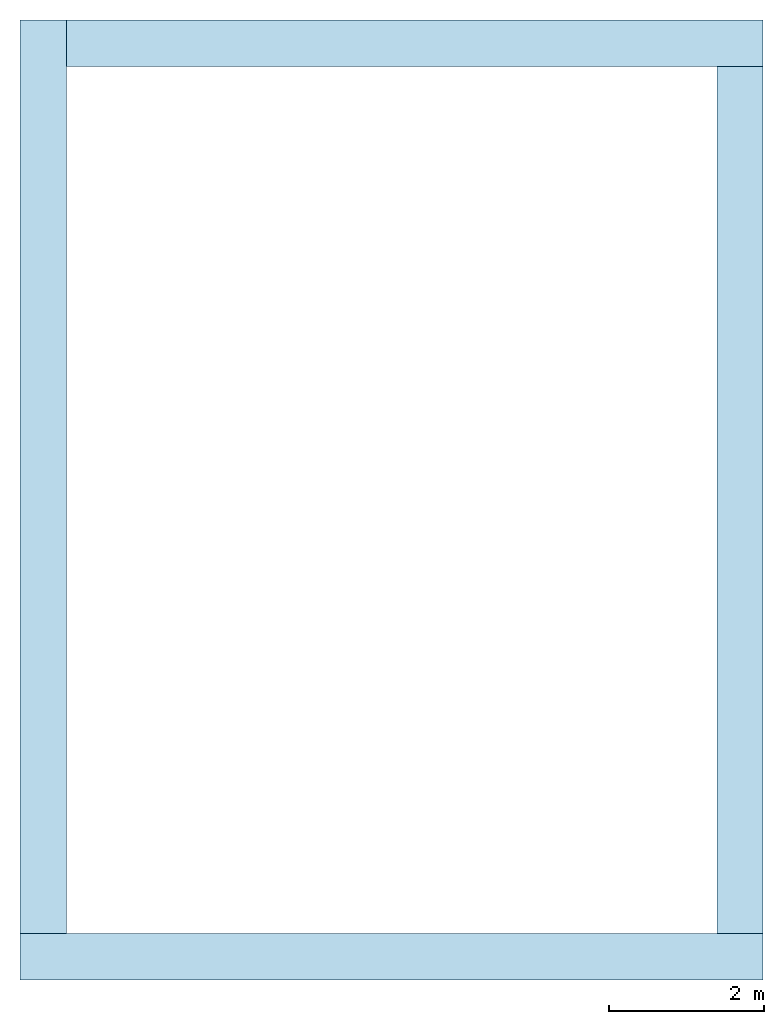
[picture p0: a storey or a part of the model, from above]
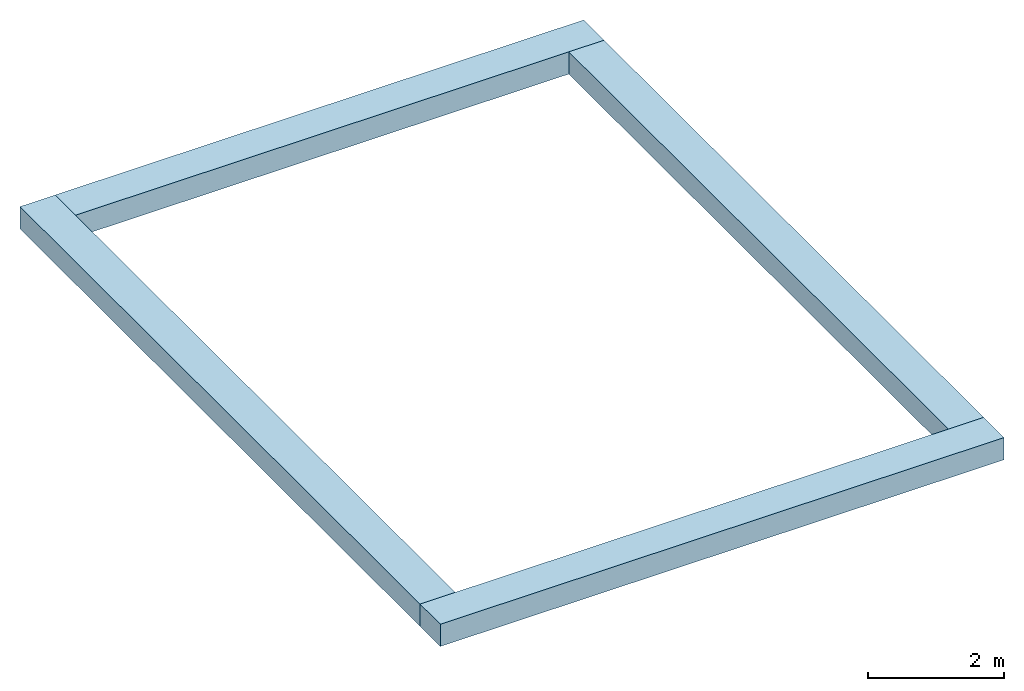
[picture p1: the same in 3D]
Properties of the parts of a building model (IFC2X3)

# File
Description: ViewDefinition [CoordinationView_V2.0], RevitIdentifiers [VersionGUID: 7e6f9387-9621-4ef8-beaa-c9e1d8378c29, NumberOfSaves: 130], CoordinateReference [CoordinateBase: Coordonnées partagées]
File name: 313 AD 1116
Time: 2024-11-04T11:44:57+01:00
Written by: ODA SDAI 23.12
Made in: Autodesk Revit 24.0.5.432 (FRA) - IFC 24.0.5.432

# IfcProject, 313 AD 1116
Phase: Etat du projet

# IfcSite, Default
RefLatitude: 42, 12, 46, 804504; RefLongitude: -71, -2, 0, -602416; RefElevation: 0 m

# IfcBuilding, MAISON D'HABITATION
LongName: MAISON D'HABITATION
Pset_BuildingCommon - NumberOfStoreys: 9

# IfcBuildingStorey: Niveau:Pointe 8 mm (14)
In: MAISON D'HABITATION
Name | LongName | Elevation (m)
Niveau .... | Niveau .... | -0.230224
Niveau ... | Niveau ... | -0.160224
Niveau .. | Niveau .. | -0.110224
Niveau dessus semelle filante | Niveau dessus semelle filante | 0.389776
Plan Réseau | Plan Réseau | 0.880776
Niveau Dalle ↑ | Niveau Dalle ↑ | 0.909776
Niveau Arase 9 | Niveau Arase 9 | 0.909776
site | site | 1.03978
Niveau coupe Menuiserie ↑ | Niveau coupe Menuiserie ↑ | 2.18978
Niveau Linteau | Niveau Linteau | 3.18978
Niveau plafond ↓ | Niveau plafond ↓ | 3.53978
Niveau ..... | Niveau ..... | 3.56978
Niveau toiture etage | Niveau toiture etage | 6.06978
Surface habitable | Surface habitable | 6.73438

# IfcSpace: Buanderie 08:3480308, 08
In: site
LongName: Buanderie; InteriorOrExteriorSpace: INTERNAL
Pset_SpaceCommon - Reference: Buanderie 08

# IfcSpace: Bureau 02:2227268, 02
In: site
LongName: Bureau; InteriorOrExteriorSpace: INTERNAL
Pset_SpaceCommon - Reference: Bureau 02

# IfcSpace: CH -1- 01:2227259, 01
In: site
LongName: CH -1-; InteriorOrExteriorSpace: INTERNAL
Pset_SpaceCommon - Reference: CH -1- 01

# IfcSpace: Dég -1- 05:2227277, 05
In: site
LongName: Dég -1-; InteriorOrExteriorSpace: INTERNAL
Pset_SpaceCommon - Reference: Dég -1- 05

# IfcSpace: Emprise au sol 09:3095654, 09
In: Niveau toiture etage
LongName: Emprise au sol; InteriorOrExteriorSpace: INTERNAL
Pset_SpaceCommon - Reference: Emprise au sol 09

# IfcSpace: Garage 07:2811163, 07
In: site
LongName: Garage; InteriorOrExteriorSpace: INTERNAL
Pset_SpaceCommon - Reference: Garage 07

# IfcSpace: SaM/Salon/Cuisine 06:2227850, 06
In: site
LongName: SaM/Salon/Cuisine; InteriorOrExteriorSpace: INTERNAL
Pset_SpaceCommon - Reference: SaM/Salon/Cuisine 06

# IfcSpace: SdB -1- 03:2227262, 03
In: site
LongName: SdB -1-; InteriorOrExteriorSpace: INTERNAL
Pset_SpaceCommon - Reference: SdB -1- 03

# IfcSpace: Surface Plancher 08:3095472, 08
In: Niveau ...
LongName: Surface Plancher; InteriorOrExteriorSpace: INTERNAL
Pset_SpaceCommon - Reference: Surface Plancher 08

# IfcSpace: Toilette 04:2227265, 04
In: site
LongName: Toilette; InteriorOrExteriorSpace: INTERNAL
Pset_SpaceCommon - Reference: Toilette 04

# IfcBuildingElementProxy: Bord de dalle:Bord des dalles, Bord de dalle:Bord des dalles:3095911
In: Plan Réseau
Pset_BuildingElementProxyCommon - Reference: Bord des dalles; sets with these values: 2

# IfcBuildingElementProxy: Bord de toiture:Bord de toiture DROIT, Bord de toiture:Bord de toiture DROIT:3165497
In: Niveau .....
Pset_BuildingElementProxyCommon - Reference: Bord de toiture DROIT; sets with these values: 2
Pset_ProvisionForVoid - Shape: Undefined; Width: 12.04 m; Height: 0.019 m; Depth: 0.019 m

# IfcBuildingElementProxy: Ossature 10:Ossature 1, Ossature 10:Ossature 1:3317750
In: Niveau .....
Type - Material: <Unnamed>
Pset_BuildingElementProxyCommon - Reference: Ossature 1; sets with these values: 2
Group: Groupe de modèles:Groupe de réseaux 2:3317774

# IfcBuildingElementProxy: Ossature 11:Ossature 1, Ossature 11:Ossature 1:3317780
In: Niveau .....
Type - Material: <Unnamed>
Pset_BuildingElementProxyCommon - Reference: Ossature 1; sets with these values: 2
Group: Groupe de modèles:Groupe de réseaux 2:3317804

# IfcBuildingElementProxy: Ossature 12:Ossature 1, Ossature 12:Ossature 1:3317810
In: Niveau .....
Type - Material: <Unnamed>
Pset_BuildingElementProxyCommon - Reference: Ossature 1; sets with these values: 2
Group: Groupe de modèles:Groupe de réseaux 2:3317834

# IfcBuildingElementProxy: Ossature 13:Ossature 1, Ossature 13:Ossature 1:3317840
In: Niveau .....
Type - Material: <Unnamed>
Pset_BuildingElementProxyCommon - Reference: Ossature 1; sets with these values: 2

# IfcBuildingElementProxy: Ossature 14:Ossature 1, Ossature 14:Ossature 1:3317870
In: Niveau .....
Type - Material: <Unnamed>
Pset_BuildingElementProxyCommon - Reference: Ossature 1; sets with these values: 2

# IfcBuildingElementProxy: Ossature 15:Ossature 1, Ossature 15:Ossature 1:3166287
In: Niveau .....
Type - Material: <Unnamed>
Pset_BuildingElementProxyCommon - Reference: Ossature 1; sets with these values: 2
Group: Groupe de modèles:Groupe de réseaux 2:3317463

# IfcBuildingElementProxy: Ossature 16:Ossature 16, Ossature 16:Ossature 16:3168144
In: Niveau .....
Type - Material: <Unnamed>
Pset_BuildingElementProxyCommon - Reference: Ossature 16; sets with these values: 2
Pset_ProvisionForVoid - Width: 0.253567 m; Height: 0.08 m; Depth: 0.08 m

# IfcBuildingElementProxy: Ossature 17:Ossature 17, Ossature 17:Ossature 17:2951754
In: Niveau .....
Type - Material: <Unnamed>
Pset_BuildingElementProxyCommon - Reference: Ossature 17; sets with these values: 2
Pset_ProvisionForVoid - Width: 0.05 m; Height: 0.05 m; Depth: 0.05 m

# IfcBuildingElementProxy: Ossature 18:Ossature 1, Ossature 18:Ossature 1:3317900
In: Niveau .....
Type - Material: <Unnamed>
Pset_BuildingElementProxyCommon - Reference: Ossature 1; sets with these values: 2
Group: Groupe de modèles:Groupe de réseaux 2:3317924

# IfcBuildingElementProxy: Ossature 1:Ossature 1, Ossature 1:Ossature 1:3317470
In: Niveau .....
Type - Material: <Unnamed>
Pset_BuildingElementProxyCommon - Reference: Ossature 1; sets with these values: 2
Group: Groupe de modèles:Groupe de réseaux 2:3317494

# IfcBuildingElementProxy: Ossature 2:Ossature 1, Ossature 2:Ossature 1:3317540
In: Niveau .....
Type - Material: <Unnamed>
Pset_BuildingElementProxyCommon - Reference: Ossature 1; sets with these values: 2
Group: Groupe de modèles:Groupe de réseaux 2:3317564

# IfcBuildingElementProxy: Ossature 3:Ossature 1, Ossature 3:Ossature 1:3317570
In: Niveau .....
Type - Material: <Unnamed>
Pset_BuildingElementProxyCommon - Reference: Ossature 1; sets with these values: 2
Group: Groupe de modèles:Groupe de réseaux 2:3317594

# IfcBuildingElementProxy: Ossature 5:Ossature 1, Ossature 5:Ossature 1:3317600
In: Niveau .....
Type - Material: <Unnamed>
Pset_BuildingElementProxyCommon - Reference: Ossature 1; sets with these values: 2

# IfcBuildingElementProxy: Ossature 6:Ossature 1, Ossature 6:Ossature 1:3317630
In: Niveau .....
Type - Material: <Unnamed>
Pset_BuildingElementProxyCommon - Reference: Ossature 1; sets with these values: 2
Group: Groupe de modèles:Groupe de réseaux 2:3317654

# IfcBuildingElementProxy: Ossature 7:Ossature 1, Ossature 7:Ossature 1:3317660
In: Niveau .....
Type - Material: <Unnamed>
Pset_BuildingElementProxyCommon - Reference: Ossature 1; sets with these values: 2
Group: Groupe de modèles:Groupe de réseaux 2:3317684

# IfcBuildingElementProxy: Ossature 8:Ossature 1, Ossature 8:Ossature 1:3317690
In: Niveau .....
Type - Material: <Unnamed>
Pset_BuildingElementProxyCommon - Reference: Ossature 1; sets with these values: 2
Group: Groupe de modèles:Groupe de réseaux 2:3317714

# IfcBuildingElementProxy: Ossature 9:Ossature 1, Ossature 9:Ossature 1:3317720
In: Niveau .....
Type - Material: <Unnamed>
Pset_BuildingElementProxyCommon - Reference: Ossature 1; sets with these values: 2
Group: Groupe de modèles:Groupe de réseaux 2:3317744

# IfcBuildingElementProxy: Sanitary_Shower-trays_Acquabella_BASE-SLATE-Shower-Tray-900x900mm:900x900, Sanitary_Shower-trays_Acquabella_BASE-SLATE-Shower-Tray-900x900mm:900x900:3091125
In: 08
Type - Material: Polyurethane - Acquabella - Fango, <Unnamed>
Type - Pset_ManufacturerTypeInformation - Manufacturer: Acquabella
Type - Pset_ProvisionForVoid - Width: 0.9 m
Classification: C1030200 Uniformat (Uniformat); Material: Polyurethane - Acquabella - Fango, PVC - Acquabella - White
Pset_BuildingElementProxyCommon - Reference: 900x900; sets with these values: 2
Pset_ProvisionForVoid - Diameter: 0.04 m

# IfcBuildingElementProxy: possition evac:possition evac (6)
Type - Material: <Unnamed>
Pset_BuildingElementProxyCommon - Reference: possition evac; sets with these values: 2
Name (possition evac:possition evac:...) | In
3359379 | 08
3359570 | 08
3360675 | 08
3361119 | 08
3361539 | Niveau dessus semelle filante
3364551 | 08

# IfcBuildingElementProxy: tableau electrique:tableau electrique, tableau electrique:tableau electrique:3371823
In: 06
Type - Material: <Unnamed>
Pset_BuildingElementProxyCommon - Reference: tableau electrique; sets with these values: 2

# IfcCovering: Plafond composé:Plafond placo + peinture, Plafond composé:Plafond placo + peinture:2856828
In: Niveau plafond ↓
Type - PredefinedType: CEILING
Type - Pset_CoveringCommon - TotalThickness: 0.02 m
Material: Plaque de mur de gypse 0.013 m, Peinture 0.007 m
Pset_CoveringCommon - Reference: Plafond placo + peinture; Finish: Peinture;
Pset_QuantityTakeOff - Reference: Plafond placo + peinture

# IfcCovering: Plafond composé:isolation 300mm, Plafond composé:isolation 300mm:3321709
In: Niveau plafond ↓
Type - PredefinedType: CEILING
Type - Pset_CoveringCommon - TotalThickness: 0.3 m
Material: Isolation Comble 0.3 m
Pset_CoveringCommon - Reference: isolation 300mm; sets with these values: 2

# IfcDistributionPort (12)
Description: Flow
Name | FlowDirection
InPort_3080776_1 | SINK
InPort_3080776_2 | SINK
Port_3083082_1 | SOURCEANDSINK
Port_3083082_2 | SOURCEANDSINK
OutPort_3091125_1 | SOURCE
InPort_3096026_1 | SINK
Port_3359379_1 | SOURCEANDSINK
Port_3359570_1 | SOURCEANDSINK
Port_3360675_1 | SOURCEANDSINK
Port_3361119_1 | SOURCEANDSINK
Port_3361539_1 | SOURCEANDSINK
Port_3364551_1 | SOURCEANDSINK

# IfcDoor: Porte Entrée 1vt:Porte Entrée 1vt - Pvc Blanc - Pleine - Sans Volet, Porte Entrée 1vt:Porte Entrée 1vt - Pvc Blanc - Pleine - Sans Volet:2856370
In: Niveau dessus semelle filante
Type - ParameterTakesPrecedence: no; Sizeable: no; Material: <Unnamed>, Acier inoxydable AISI 304, K.Line Tendance Gris sablé (2900) - NX, Verre sablé, K.Line Vintage Anodisé Argent - AC
Type - Pset_DoorCommon - IsExternal: yes
Type - Pset_ManufacturerTypeInformation - Manufacturer: K.LINE
OverallHeight: 2.282 m; OverallWidth: 1.382 m; Classification: B2030110 Uniformat (Uniformat)
Pset_DoorCommon - Reference: Porte Entrée 1vt - Pvc Blanc - Pleine - Sans Volet
Pset_QuantityTakeOff - Reference: Porte Entrée 1vt - Pvc Blanc - Pleine - Sans Volet

# IfcDoor: Porte a galandage 1V eclisse:L=900xH=2100, Porte a galandage 1V eclisse:L=900xH=2100:3480355
In: site
Type - ParameterTakesPrecedence: no; Sizeable: no; Material: Alluminio, Pioppo, Acciaio, Galvanizzato
Type - Pset_DoorCommon - IsExternal: no
Type - Pset_ManufacturerTypeInformation - Manufacturer: ECLISSE
OverallHeight: 2.343 m; OverallWidth: 1.95 m
Pset_DoorCommon - Reference: L=900xH=2100
Pset_QuantityTakeOff - Reference: L=900xH=2100

# IfcDoor: porte intérieur Simple reservation 13 cm:80 x 204 (5)
In: site
Type - ParameterTakesPrecedence: no; Sizeable: no; Material: Poignée Porte, Dormants Portes, Panneaux Portes
Type - Pset_DoorCommon - IsExternal: no
OverallHeight: 2.225 m; OverallWidth: 0.9 m
Pset_DoorCommon - Reference: 80 x 204
Pset_QuantityTakeOff - Reference: 80 x 204
Name (porte intérieur Simple reservation 13 cm:80 x 204:...)
2960167
2960308
2960327
2960359
2960386

# IfcFlowController: IS_IdealrainDual_A5691_BIM_FR:A5691AA - Idealrain Dual Shower System - M1 Rainshower - Fixer Risers - M3 Handspray & Diverter for expoded mixer, IS_IdealrainDual_A5691_BIM_FR:A5691AA - Idealrain Dual Shower System - M1 Rainshower - Fixer Risers - M3 Handspray & Diverter for expoded mixer:3095962
In: 03
Type - Material: ISI_IdealStandard_Brassware_Rubber_Render, ISI_IdealStandard_Brassware_Chrome_render
Type - Pset_ManufacturerTypeInformation - Manufacturer: prescription@idealstandard.fr
Classification: C1030200 Uniformat (Uniformat)
Pset_DistributionFlowElementCommon - Reference: A5691AA - Idealrain Dual Shower System - M1 Rainshower - Fixer Risers - M3 Handspray & Diverter for expoded mixer; sets with these values: 2

# IfcFlowController: Robinet extérieur:1/2, Robinet extérieur:1/2:3096026
In: 07
Type - PredefinedType: FAUCET; Material: <Unnamed>
Pset_DistributionFlowElementCommon - Reference: 1/2; sets with these values: 2

# IfcFlowSegment: Gouttière:Gouttière:41283, Gouttière:Gouttière:3165652
In: Niveau .....
Type - ElementType: Gouttière:Gouttière:41283; PredefinedType: GUTTER
Pset_DistributionFlowElementCommon - Reference: Gouttière; sets with these values: 2
Pset_FlowSegmentDuctSegment - Length: 12.04 m; sets with these values: 2
Pset_PipeSegmentTypeGutter - Slope: 0 deg

# IfcFlowTerminal: Descente Gouttière rectangle:Descente Gouttière rectangle (2)
In: Niveau Dalle ↑
Type - Material: <Unnamed>
Pset_DistributionFlowElementCommon - Reference: Descente Gouttière rectangle; sets with these values: 2
Name (Descente Gouttière rectangle:Descente Gouttière rectangle:...)
3099253
3102723

# IfcFlowTerminal: TAP MIXER, SINGLE LEVER:TAPWARE - ACCESSIBLE BASIN MIXER, TAP MIXER, SINGLE LEVER:TAPWARE - ACCESSIBLE BASIN MIXER:3080776
In: 06
Type - Material: Metal - Steel - Stainless - Chrome, Metal - Steel
Pset_DistributionFlowElementCommon - Reference: TAPWARE - ACCESSIBLE BASIN MIXER; sets with these values: 2

# IfcFlowTerminal: Toilette standard:TOILET SUITE - STANDARD, Toilette standard:TOILET SUITE - STANDARD:3083082
In: 08
Type - Material: <Unnamed>
Pset_DistributionFlowElementCommon - Reference: TOILET SUITE - STANDARD; sets with these values: 2

# IfcFooting: Semelle filante:Soubassement de soutènement - 300 x 600 x 300 (4)
In: Niveau ..
PredefinedType: STRIP_FOOTING; Classification: A1010110 Uniformat (Uniformat); Material: Béton, coulé sur place
Pset_QuantityTakeOff - Reference: Soubassement de soutènement - 300 x 600 x 300; sets with these values: 3
Name (Semelle filante:Soubassement de soutènement - 300 x 600 x 300:...)
2856357
2856359
2856361
2856363

# IfcFurnishingElement: Cuisine meuble evier:Cuisine meuble evier, Cuisine meuble evier:Cuisine meuble evier:3080772
In: 06
Type - Material: Blue, Red, <Unnamed>
Pset_QuantityTakeOff - Reference: Cuisine meuble evier

# IfcFurnishingElement: DRAWER UNITS:CUPBOARD DRAWER UNITS 450W, DRAWER UNITS:CUPBOARD DRAWER UNITS 450W:3080773
In: 08
Type - Material: <Unnamed>
Type - Pset_FurnitureTypeCommon - Description: Cupboard - drawer unit
Pset_QuantityTakeOff - Reference: CUPBOARD DRAWER UNITS 450W

# IfcFurnishingElement: FLOOR CUPBOARD WITH ADJUSTABLE SHELVES - DOUBLE:CUPBOARD - UNDERBENCH (2)
In: 08
Type - Material: <Unnamed>
Type - Pset_FurnitureTypeCommon - Description: Cupboard: under bench
Pset_QuantityTakeOff - Reference: CUPBOARD - UNDERBENCH
Name (FLOOR CUPBOARD WITH ADJUSTABLE SHELVES - DOUBLE:CUPBOARD - UNDERBENCH:...)
3080774
3080775

# IfcFurnishingElement: Lit:Lit, Lit:Lit:3081082
In: 08
Type - Material: <Unnamed>
Type - Pset_FurnitureTypeCommon - Description: Mattress - foam
Pset_QuantityTakeOff - Reference: Lit

# IfcFurnishingElement: SdB meuble 1V:Default, SdB meuble 1V:Default:3082863
In: site
Type - Material: Chrome 82CBA5A1
Material: Chrome 82CBA5A1, Aluminium A4B6EB3E, Mirror 308DF55D, Light 24AFE332, WG 7007EC7, Ceramic-White F17BDE45, Chrome FF203585
Pset_QuantityTakeOff - Reference: Default

# IfcFurnishingElement: porte de placard:porte de placard 2.40, porte de placard:porte de placard 2.40:3081854
In: 06
Type - Material: Aluminuim blanc, Stratifié, bleu marine
Pset_QuantityTakeOff - Reference: porte de placard 2.40

# IfcOpeningElement: Opening (20)
Name | In
Mur de base:OSB 0.18m:2856309 | Niveau dessus semelle filante | Pset_OpeningElementCommon - Reference: 80 x 204; sets with these values: 2
Mur de base:mur interieur 7 cm:2856311 | Niveau Dalle ↑ | Pset_OpeningElementCommon - Reference: 80 x 204; sets with these values: 2
Mur de base:mur interieur 7 cm:2856312 | Niveau Dalle ↑ | Pset_OpeningElementCommon - Reference: 80 x 204; sets with these values: 2
Mur de base:mur interieur 7 cm:2856314 | Niveau Dalle ↑ | Pset_OpeningElementCommon - Reference: 80 x 204; sets with these values: 2
Mur de base:mur interieur 7 cm:2856315 | Niveau Dalle ↑ | Pset_OpeningElementCommon - Reference: 80 x 204; sets with these values: 2
Mur de base:Mur Invisible = 0.80m:3105446 | site | Pset_OpeningElementCommon - Reference: Baie coulissante 2V - Alu Blanc - Volet apparent electrique; sets with these values: 2
Mur de base:Mur Invisible = 0.80m:3105446 | site | Pset_OpeningElementCommon - Reference: Fenetre 2V - PVC blanc - OV/OB - Volet electrique apparent; sets with these values: 2
3 x Mur de base:isolation+placo+peinture 14cm:2856305 | Niveau dessus semelle filante
2 x Mur de base:isolation+placo+peinture 14cm:2856306 | Niveau dessus semelle filante
porte intérieur Simple reservation 13 cm:80 x 204:2960386:1 | Niveau dessus semelle filante
Mur de base:isolation+placo+peinture 14cm:2856308 | Niveau dessus semelle filante
porte intérieur Simple reservation 13 cm:80 x 204:2960359:1 | Niveau Dalle ↑
porte intérieur Simple reservation 13 cm:80 x 204:2960308:1 | Niveau Dalle ↑
porte intérieur Simple reservation 13 cm:80 x 204:2960327:1 | Niveau Dalle ↑
porte intérieur Simple reservation 13 cm:80 x 204:2960167:1 | Niveau Dalle ↑
porte garage sectionnel:Portail sectionnel Electrique aluminuim:2946641:1 | Niveau dessus semelle filante
Mur de base:mur interieur 7 cm:3479720 | site

# IfcRoof: Toit de base:Toit Tuile 100mm, Toit de base:Toit Tuile 100mm:2948752
In: Niveau toiture etage
Material: 38f2b84c_59a0_493e_94eb_272e1fd0c87f 0.1 m
Pset_QuantityTakeOff - Reference: Toit Tuile 100mm
Pset_RoofCommon - IsExternal: yes; Reference: Toit Tuile 100mm; ProjectedArea: 110.768 m2; TotalArea: 114.179 m2

# IfcSlab: Sol:dalle beton 12cm, Sol:dalle beton 12cm:2856296
In: Niveau dessus semelle filante
Type - PredefinedType: FLOOR; Material: Béton, coulé sur place 0.12 m
Type - Pset_SlabCommon - IsExternal: no; ThermalTransmittance: 8.71667 kg/K/s3
Pset_QuantityTakeOff - Reference: dalle beton 12cm; sets with these values: 2
Pset_SlabCommon - Reference: dalle beton 12cm; LoadBearing: no; PitchAngle: 0 deg

# IfcSlab: Sol:plancher chauffant+chape+carrelage = 0.13m, Sol:plancher chauffant+chape+carrelage = 0.13m:2856322
In: Niveau dessus semelle filante
Type - PredefinedType: FLOOR; Material: Carrelage 40 x 40 0.015 m, Béton - Chape liquide 0.055 m, Isolant rigide 0.06 m
Type - Pset_SlabCommon - IsExternal: no; ThermalTransmittance: 0.578494 kg/K/s3
Pset_QuantityTakeOff - Reference: plancher chauffant+chape+carrelage = 0.13m; sets with these values: 2
Pset_SlabCommon - LoadBearing: no; PitchAngle: 0 deg; Reference: plancher chauffant+chape+carrelage = 0.13m

# IfcSlab: Toit de base:Toit Tuile 100mm (2)
In: Niveau toiture etage
Type - PredefinedType: ROOF
Type - Pset_SlabCommon - IsExternal: yes
Material: 38f2b84c_59a0_493e_94eb_272e1fd0c87f 0.1 m
Pset_QuantityTakeOff - Reference: Toit Tuile 100mm; sets with these values: 2
Pset_SlabCommon - Reference: Toit Tuile 100mm; PitchAngle: 14.04 deg

# IfcWall: Mur de base:parpaing+enduit 18cm (4)
In: Niveau dessus semelle filante
Type - PredefinedType: STANDARD; Material: Enduit gratté 0.018 m, Agglo creux, parpaing 0.2 m
Type - Pset_WallCommon - IsExternal: yes; ThermalTransmittance: 4.62525 kg/K/s3
Pset_QuantityTakeOff - Reference: parpaing+enduit 18cm; sets with these values: 2
Pset_WallCommon - LoadBearing: no; Reference: parpaing+enduit 18cm; ExtendToStructure: no
Name (Mur de base:parpaing+enduit 18cm:...)
2856301
2856302
2856303
2856304

# IfcWallStandardCase: Mur de base:Générique - 200 mm (4)
In: Niveau dessus semelle filante
Type - PredefinedType: STANDARD; Material: Mur par défaut 0.2 m
Type - Pset_WallCommon - IsExternal: yes
Pset_QuantityTakeOff - Reference: Générique - 200 mm; sets with these values: 2
Pset_WallCommon - LoadBearing: no; Reference: Générique - 200 mm
Name (Mur de base:Générique - 200 mm:...) | ExtendToStructure
2856353 | no
2856354 | yes
2856355 | yes
2856356 | yes

# IfcWallStandardCase: Mur de base:Mur Invisible = 0.80m, Mur de base:Mur Invisible = 0.80m:3105446
In: site
Type - PredefinedType: STANDARD; Material: Invisible 0.08 m
Type - Pset_WallCommon - IsExternal: yes; ThermalTransmittance: 13.075 kg/K/s3
Pset_QuantityTakeOff - Reference: Mur Invisible = 0.80m; sets with these values: 2
Pset_WallCommon - LoadBearing: no; ExtendToStructure: no; Reference: Mur Invisible = 0.80m

# IfcWallStandardCase: Mur de base:OSB 0.18m, Mur de base:OSB 0.18m:2856309
In: Niveau dessus semelle filante
Type - PredefinedType: STANDARD; Material: Osb 0.18m 0.018 m
Type - Pset_WallCommon - IsExternal: no; ThermalTransmittance: 6.66667 kg/K/s3
Pset_QuantityTakeOff - Reference: OSB 0.18m; sets with these values: 2
Pset_WallCommon - LoadBearing: no; ExtendToStructure: no; Reference: OSB 0.18m

# IfcWallStandardCase: Mur de base:isolation+placo+peinture 14cm (3)
In: Niveau dessus semelle filante
Type - PredefinedType: STANDARD; Material: Isolation 0.12 m, Plaque de mur de gypse 0.013 m, Peinture 0.007 m
Type - Pset_WallCommon - IsExternal: no; ThermalTransmittance: 0.281737 kg/K/s3
Pset_QuantityTakeOff - Reference: isolation+placo+peinture 14cm; sets with these values: 2
Pset_WallCommon - LoadBearing: no; ExtendToStructure: no; Reference: isolation+placo+peinture 14cm
Name (Mur de base:isolation+placo+peinture 14cm:...)
2856305
2856306
2856308

# IfcWallStandardCase: Mur de base:isolation+placo+peinture 20cm, Mur de base:isolation+placo+peinture 20cm:2856307
In: Niveau dessus semelle filante
Type - PredefinedType: STANDARD; Material: Isolation 0.18m 0.18 m, Plaque de mur de gypse 0.013 m, Peinture 0.007 m
Type - Pset_WallCommon - IsExternal: no; ThermalTransmittance: 0.188178 kg/K/s3
Pset_QuantityTakeOff - Reference: isolation+placo+peinture 20cm; sets with these values: 2
Pset_WallCommon - LoadBearing: no; ExtendToStructure: no; Reference: isolation+placo+peinture 20cm

# IfcWallStandardCase: Mur de base:mur interieur 7 cm (10)
Type - PredefinedType: STANDARD; Material: Peinture 0.007 m, Plaque de mur de gypse 0.013 m, Isolation 0.03 m, Plaque de mur de gypse 0.013 m, Peinture 0.007 m
Type - Pset_WallCommon - IsExternal: no; ThermalTransmittance: 1.08418 kg/K/s3
Pset_QuantityTakeOff - Reference: mur interieur 7 cm; sets with these values: 2
Pset_WallCommon - LoadBearing: no; ExtendToStructure: no; Reference: mur interieur 7 cm
Name (Mur de base:mur interieur 7 cm:...) | In
2856311 | Niveau Dalle ↑
2856312 | Niveau Dalle ↑
2856313 | Niveau Dalle ↑
2856314 | Niveau Dalle ↑
2856315 | Niveau Dalle ↑
2856316 | Niveau Dalle ↑
2856317 | Niveau Dalle ↑
2957069 | Niveau Dalle ↑
2958450 | Niveau Dalle ↑
3479720 | site

# IfcWindow: Bloc baie et fenetre Classic thermobloc:Fenetre 2V - PVC blanc - OV/OB - Volet electrique apparent (3)
In: Niveau dessus semelle filante
Type - ParameterTakesPrecedence: no; Sizeable: no; Material: <Unnamed>, K.Line Intemporel Taupe (7022 S) - JK, K.Line Intemporel Blanc satiné (9016 S) - KQ, BUBENDORFF - 100 (RAL 9016), Verre, K.Line Tendance Gris sablé (2900) - NX, K.Line Accessoire Blanc - KQ
Type - Pset_ManufacturerTypeInformation - Manufacturer: K.LINE
Type - Pset_WindowCommon - IsExternal: no
OverallHeight: 1.5755 m; OverallWidth: 2.09561 m; Classification: B2020110 Uniformat (Uniformat)
Pset_QuantityTakeOff - Reference: Fenetre 2V - PVC blanc - OV/OB - Volet electrique apparent
Pset_WindowCommon - Reference: Fenetre 2V - PVC blanc - OV/OB - Volet electrique apparent
Name (Bloc baie et fenetre Classic thermobloc:Fenetre 2V - PVC blanc - OV/OB - Volet electrique apparent:...)
2856448
2856450
3481115

# IfcWindow: Fenêtre coulissante 2 Rails et 2 Vantaux Classic et Thermobloc:Baie coulissante 2V - Alu Blanc - Volet apparent electrique, Fenêtre coulissante 2 Rails et 2 Vantaux Classic et Thermobloc:Baie coulissante 2V - Alu Blanc - Volet apparent electrique:2856447
In: site
Type - ParameterTakesPrecedence: no; Sizeable: no; Material: <Unnamed>, K.Line Intemporel Blanc satiné (9016 S) - KQ, SPPF - Blanc (RAL 9016), Verre, K.Line Accessoire Blanc - KQ, K.Line Tendance Gris sablé (2900) - NX
Type - Pset_ManufacturerTypeInformation - Manufacturer: K.LINE
Type - Pset_WindowCommon - IsExternal: no
OverallHeight: 2.86433 m; OverallWidth: 3.644 m; Classification: B2020110 Uniformat (Uniformat)
Pset_QuantityTakeOff - Reference: Baie coulissante 2V - Alu Blanc - Volet apparent electrique
Pset_WindowCommon - Reference: Baie coulissante 2V - Alu Blanc - Volet apparent electrique

# IfcWindow: Fenêtre coulissante 2 Rails et 2 Vantaux Classic et Thermobloc:Fenêtre coulissante 2V - PVC blanc - Volet electrique apparent, Fenêtre coulissante 2 Rails et 2 Vantaux Classic et Thermobloc:Fenêtre coulissante 2V - PVC blanc - Volet electrique apparent:2856451
In: Niveau dessus semelle filante
Type - ParameterTakesPrecedence: no; Sizeable: no; Material: <Unnamed>, K.Line Intemporel Blanc satiné (9016 S) - KQ, SPPF - Blanc (RAL 9016), Verre, K.Line Accessoire Blanc - KQ, K.Line Tendance Gris sablé (2900) - NX
Type - Pset_ManufacturerTypeInformation - Manufacturer: K.LINE
Type - Pset_WindowCommon - IsExternal: no
OverallHeight: 1.39767 m; OverallWidth: 2.144 m; Classification: B2020110 Uniformat (Uniformat)
Pset_QuantityTakeOff - Reference: Fenêtre coulissante 2V - PVC blanc - Volet electrique apparent
Pset_WindowCommon - Reference: Fenêtre coulissante 2V - PVC blanc - Volet electrique apparent

# IfcWindow: Porte fenetre sans volet:Fenetre 2V - PVC blanc - OV/OB - Volet electrique apparent - Verre imprimé, Porte fenetre sans volet:Fenetre 2V - PVC blanc - OV/OB - Volet electrique apparent - Verre imprimé:3058240
In: site
Type - ParameterTakesPrecedence: no; Sizeable: no; Material: <Unnamed>, K.Line Accessoires Aspect Inox - TD, Verre, K.Line Tendance Grège (9007 T) - RQ, K.Line Tendance Gris sablé (2900) - NX, Bois
Type - Pset_ManufacturerTypeInformation - Manufacturer: K.LINE
Type - Pset_WindowCommon - IsExternal: no
OverallHeight: 1.018 m; OverallWidth: 1.82361 m; Classification: B2020110 Uniformat (Uniformat)
Pset_QuantityTakeOff - Reference: Fenetre 2V - PVC blanc - OV/OB - Volet electrique apparent - Verre imprimé
Pset_WindowCommon - Reference: Fenetre 2V - PVC blanc - OV/OB - Volet electrique apparent - Verre imprimé

# IfcWindow: porte garage sectionnel:Portail sectionnel Electrique aluminuim, porte garage sectionnel:Portail sectionnel Electrique aluminuim:2946641
In: site
Type - ParameterTakesPrecedence: no; Sizeable: no; Material: Structure Dark
Type - Pset_WindowCommon - IsExternal: no
OverallHeight: 2 m; OverallWidth: 2.4 m; Material: Structure Dark, Structure Light, Black, <Unnamed>
Pset_QuantityTakeOff - Reference: Portail sectionnel Electrique aluminuim
Pset_WindowCommon - IsExternal: yes; Reference: Portail sectionnel Electrique aluminuim
